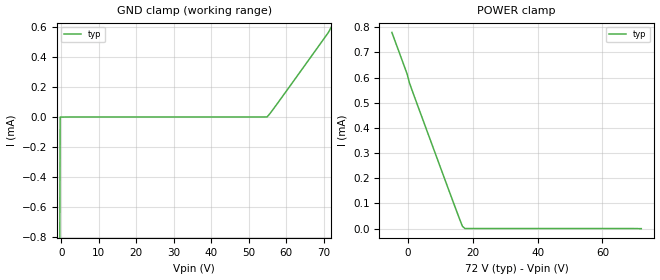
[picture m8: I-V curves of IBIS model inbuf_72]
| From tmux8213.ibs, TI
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| inbuf_72
[Model]   inbuf_72
Model_type   Input
Vinl = 0.8
Vinh = 1.3
|   typ   min   max
C_comp   1.598234e-13   NA   NA
[Voltage Range]   72   NA   NA
[Temperature Range]   27   NA   NA
[Power Clamp Reference]   72   NA   NA
[GND Clamp Reference]   0   NA   NA
[GND Clamp]
|   Voltage   I(typ)   I(min)   I(max)
-5V       -116.5mA   NA         NA
-1.111V   -6.984mA   NA         NA
-333.3mV  -221nA     NA         NA
54.89V    1.038uA    NA         NA
58V       103.6uA    NA         NA
70.44V    538uA      NA         NA
72V       600.8uA    NA         NA
[POWER Clamp]
|   Voltage   I(typ)   I(min)   I(max)
-5V       779.1uA    NA         NA
-333.3mV  615.5uA    NA         NA
444.4mV   578.1uA    NA         NA
1.222V    549.7uA    NA         NA
14.44V    88.24uA    NA         NA
16.78V    9.56uA     NA         NA
17.56V    555.2nA    NA         NA
72V       -220pA     NA         NA
